VERSION 5.7 ;
  NOWIREEXTENSIONATPIN ON ;
  DIVIDERCHAR "/" ;
  BUSBITCHARS "[]" ;
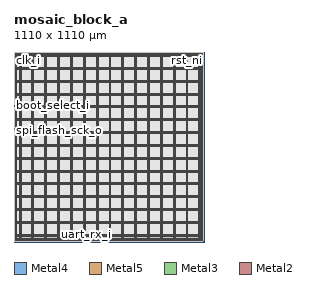
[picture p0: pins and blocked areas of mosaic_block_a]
MACRO mosaic_block_a
  CLASS BLOCK ;
  FOREIGN mosaic_block_a ;
  ORIGIN 0.000 0.000 ;
  SIZE 1110.000 BY 1110.000 ;
  PIN VDD
    DIRECTION INOUT ;
    USE POWER ;
    PORT
      LAYER Metal4 ;
        RECT 11.240 14.600 14.240 1098.680 ;
    END
    PORT
      LAYER Metal4 ;
        RECT 1095.680 14.600 1098.680 1098.680 ;
    END
    PORT
      LAYER Metal5 ;
        RECT 11.240 14.600 1098.680 17.600 ;
    END
    PORT
      LAYER Metal5 ;
        RECT 11.240 1095.680 1098.680 1098.680 ;
    END
    PORT
      LAYER Metal4 ;
        RECT 30.060 9.600 35.060 1103.680 ;
    END
    PORT
      LAYER Metal4 ;
        RECT 105.060 9.600 110.060 1103.680 ;
    END
    PORT
      LAYER Metal4 ;
        RECT 180.060 9.600 185.060 1103.680 ;
    END
    PORT
      LAYER Metal4 ;
        RECT 255.060 9.600 260.060 1103.680 ;
    END
    PORT
      LAYER Metal4 ;
        RECT 330.060 9.600 335.060 1103.680 ;
    END
    PORT
      LAYER Metal4 ;
        RECT 405.060 9.600 410.060 1103.680 ;
    END
    PORT
      LAYER Metal4 ;
        RECT 480.060 9.600 485.060 1103.680 ;
    END
    PORT
      LAYER Metal4 ;
        RECT 555.060 9.600 560.060 1103.680 ;
    END
    PORT
      LAYER Metal4 ;
        RECT 630.060 9.600 635.060 1103.680 ;
    END
    PORT
      LAYER Metal4 ;
        RECT 705.060 9.600 710.060 1103.680 ;
    END
    PORT
      LAYER Metal4 ;
        RECT 780.060 9.600 785.060 1103.680 ;
    END
    PORT
      LAYER Metal4 ;
        RECT 855.060 9.600 860.060 1103.680 ;
    END
    PORT
      LAYER Metal4 ;
        RECT 930.060 9.600 935.060 1103.680 ;
    END
    PORT
      LAYER Metal4 ;
        RECT 1005.060 9.600 1010.060 1103.680 ;
    END
    PORT
      LAYER Metal4 ;
        RECT 1080.060 9.600 1085.060 1103.680 ;
    END
    PORT
      LAYER Metal5 ;
        RECT 6.240 33.750 1103.680 38.750 ;
    END
    PORT
      LAYER Metal5 ;
        RECT 6.240 108.750 1103.680 113.750 ;
    END
    PORT
      LAYER Metal5 ;
        RECT 6.240 183.750 1103.680 188.750 ;
    END
    PORT
      LAYER Metal5 ;
        RECT 6.240 258.750 1103.680 263.750 ;
    END
    PORT
      LAYER Metal5 ;
        RECT 6.240 333.750 1103.680 338.750 ;
    END
    PORT
      LAYER Metal5 ;
        RECT 6.240 408.750 1103.680 413.750 ;
    END
    PORT
      LAYER Metal5 ;
        RECT 6.240 483.750 1103.680 488.750 ;
    END
    PORT
      LAYER Metal5 ;
        RECT 6.240 558.750 1103.680 563.750 ;
    END
    PORT
      LAYER Metal5 ;
        RECT 6.240 633.750 1103.680 638.750 ;
    END
    PORT
      LAYER Metal5 ;
        RECT 6.240 708.750 1103.680 713.750 ;
    END
    PORT
      LAYER Metal5 ;
        RECT 6.240 783.750 1103.680 788.750 ;
    END
    PORT
      LAYER Metal5 ;
        RECT 6.240 858.750 1103.680 863.750 ;
    END
    PORT
      LAYER Metal5 ;
        RECT 6.240 933.750 1103.680 938.750 ;
    END
    PORT
      LAYER Metal5 ;
        RECT 6.240 1008.750 1103.680 1013.750 ;
    END
    PORT
      LAYER Metal5 ;
        RECT 6.240 1083.750 1103.680 1088.750 ;
    END
  END VDD
  PIN VSS
    DIRECTION INOUT ;
    USE GROUND ;
    PORT
      LAYER Metal4 ;
        RECT 6.240 9.600 9.240 1103.680 ;
    END
    PORT
      LAYER Metal4 ;
        RECT 1100.680 9.600 1103.680 1103.680 ;
    END
    PORT
      LAYER Metal5 ;
        RECT 6.240 9.600 1103.680 12.600 ;
    END
    PORT
      LAYER Metal5 ;
        RECT 6.240 1100.680 1103.680 1103.680 ;
    END
    PORT
      LAYER Metal4 ;
        RECT 36.060 9.600 41.060 1103.680 ;
    END
    PORT
      LAYER Metal4 ;
        RECT 111.060 9.600 116.060 1103.680 ;
    END
    PORT
      LAYER Metal4 ;
        RECT 186.060 9.600 191.060 1103.680 ;
    END
    PORT
      LAYER Metal4 ;
        RECT 261.060 9.600 266.060 1103.680 ;
    END
    PORT
      LAYER Metal4 ;
        RECT 336.060 9.600 341.060 1103.680 ;
    END
    PORT
      LAYER Metal4 ;
        RECT 411.060 9.600 416.060 1103.680 ;
    END
    PORT
      LAYER Metal4 ;
        RECT 486.060 9.600 491.060 1103.680 ;
    END
    PORT
      LAYER Metal4 ;
        RECT 561.060 9.600 566.060 1103.680 ;
    END
    PORT
      LAYER Metal4 ;
        RECT 636.060 9.600 641.060 1103.680 ;
    END
    PORT
      LAYER Metal4 ;
        RECT 711.060 9.600 716.060 1103.680 ;
    END
    PORT
      LAYER Metal4 ;
        RECT 786.060 9.600 791.060 1103.680 ;
    END
    PORT
      LAYER Metal4 ;
        RECT 861.060 9.600 866.060 1103.680 ;
    END
    PORT
      LAYER Metal4 ;
        RECT 936.060 9.600 941.060 1103.680 ;
    END
    PORT
      LAYER Metal4 ;
        RECT 1011.060 9.600 1016.060 1103.680 ;
    END
    PORT
      LAYER Metal4 ;
        RECT 1086.060 9.600 1091.060 1103.680 ;
    END
    PORT
      LAYER Metal5 ;
        RECT 6.240 39.750 1103.680 44.750 ;
    END
    PORT
      LAYER Metal5 ;
        RECT 6.240 114.750 1103.680 119.750 ;
    END
    PORT
      LAYER Metal5 ;
        RECT 6.240 189.750 1103.680 194.750 ;
    END
    PORT
      LAYER Metal5 ;
        RECT 6.240 264.750 1103.680 269.750 ;
    END
    PORT
      LAYER Metal5 ;
        RECT 6.240 339.750 1103.680 344.750 ;
    END
    PORT
      LAYER Metal5 ;
        RECT 6.240 414.750 1103.680 419.750 ;
    END
    PORT
      LAYER Metal5 ;
        RECT 6.240 489.750 1103.680 494.750 ;
    END
    PORT
      LAYER Metal5 ;
        RECT 6.240 564.750 1103.680 569.750 ;
    END
    PORT
      LAYER Metal5 ;
        RECT 6.240 639.750 1103.680 644.750 ;
    END
    PORT
      LAYER Metal5 ;
        RECT 6.240 714.750 1103.680 719.750 ;
    END
    PORT
      LAYER Metal5 ;
        RECT 6.240 789.750 1103.680 794.750 ;
    END
    PORT
      LAYER Metal5 ;
        RECT 6.240 864.750 1103.680 869.750 ;
    END
    PORT
      LAYER Metal5 ;
        RECT 6.240 939.750 1103.680 944.750 ;
    END
    PORT
      LAYER Metal5 ;
        RECT 6.240 1014.750 1103.680 1019.750 ;
    END
    PORT
      LAYER Metal5 ;
        RECT 6.240 1089.750 1103.680 1094.750 ;
    END
  END VSS
  PIN boot_select_i
    DIRECTION INPUT ;
    USE SIGNAL ;
    ANTENNAGATEAREA 0.396000 ;
    PORT
      LAYER Metal3 ;
        RECT 0.000 796.320 0.560 796.880 ;
    END
  END boot_select_i
  PIN clk_i
    DIRECTION INPUT ;
    USE SIGNAL ;
    ANTENNAGATEAREA 9.476000 ;
    PORT
      LAYER Metal3 ;
        RECT 0.000 1087.520 0.560 1088.080 ;
    END
  END clk_i
  PIN execute_from_flash_i
    DIRECTION INPUT ;
    USE SIGNAL ;
    ANTENNAGATEAREA 0.396000 ;
    PORT
      LAYER Metal3 ;
        RECT 0.000 778.400 0.560 778.960 ;
    END
  END execute_from_flash_i
  PIN rst_ni
    DIRECTION INPUT ;
    USE SIGNAL ;
    ANTENNAGATEAREA 0.396000 ;
    PORT
      LAYER Metal2 ;
        RECT 1030.400 1109.440 1030.960 1110.000 ;
    END
  END rst_ni
  PIN spi_flash_cs_o
    DIRECTION OUTPUT ;
    USE SIGNAL ;
    ANTENNADIFFAREA 0.897600 ;
    PORT
      LAYER Metal3 ;
        RECT 0.000 658.560 0.560 659.120 ;
    END
  END spi_flash_cs_o
  PIN spi_flash_sck_o
    DIRECTION OUTPUT ;
    USE SIGNAL ;
    ANTENNADIFFAREA 0.897600 ;
    PORT
      LAYER Metal3 ;
        RECT 0.000 649.600 0.560 650.160 ;
    END
  END spi_flash_sck_o
  PIN spi_flash_sd_io[0]
    DIRECTION INOUT ;
    USE SIGNAL ;
    ANTENNAGATEAREA 2.204000 ;
    ANTENNADIFFAREA 2.074800 ;
    PORT
      LAYER Metal3 ;
        RECT 0.000 659.680 0.560 660.240 ;
    END
  END spi_flash_sd_io[0]
  PIN spi_flash_sd_io[1]
    DIRECTION INOUT ;
    USE SIGNAL ;
    ANTENNAGATEAREA 2.204000 ;
    ANTENNADIFFAREA 2.074800 ;
    PORT
      LAYER Metal3 ;
        RECT 0.000 657.440 0.560 658.000 ;
    END
  END spi_flash_sd_io[1]
  PIN spi_flash_sd_io[2]
    DIRECTION INOUT ;
    USE SIGNAL ;
    ANTENNAGATEAREA 2.204000 ;
    ANTENNADIFFAREA 2.074800 ;
    PORT
      LAYER Metal3 ;
        RECT 0.000 656.320 0.560 656.880 ;
    END
  END spi_flash_sd_io[2]
  PIN spi_flash_sd_io[3]
    DIRECTION INOUT ;
    USE SIGNAL ;
    ANTENNAGATEAREA 2.204000 ;
    ANTENNADIFFAREA 2.074800 ;
    PORT
      LAYER Metal3 ;
        RECT 0.000 652.960 0.560 653.520 ;
    END
  END spi_flash_sd_io[3]
  PIN status_o[0]
    DIRECTION OUTPUT ;
    USE SIGNAL ;
    ANTENNADIFFAREA 0.897600 ;
    PORT
      LAYER Metal3 ;
        RECT 0.000 795.200 0.560 795.760 ;
    END
  END status_o[0]
  PIN status_o[1]
    DIRECTION OUTPUT ;
    USE SIGNAL ;
    ANTENNADIFFAREA 0.897600 ;
    PORT
      LAYER Metal3 ;
        RECT 0.000 803.040 0.560 803.600 ;
    END
  END status_o[1]
  PIN status_o[2]
    DIRECTION OUTPUT ;
    USE SIGNAL ;
    ANTENNADIFFAREA 0.897600 ;
    PORT
      LAYER Metal3 ;
        RECT 0.000 801.920 0.560 802.480 ;
    END
  END status_o[2]
  PIN status_o[3]
    DIRECTION OUTPUT ;
    USE SIGNAL ;
    ANTENNADIFFAREA 0.897600 ;
    PORT
      LAYER Metal3 ;
        RECT 0.000 736.960 0.560 737.520 ;
    END
  END status_o[3]
  PIN status_o[4]
    DIRECTION OUTPUT ;
    USE SIGNAL ;
    ANTENNADIFFAREA 0.897600 ;
    PORT
      LAYER Metal3 ;
        RECT 0.000 769.440 0.560 770.000 ;
    END
  END status_o[4]
  PIN status_o[5]
    DIRECTION OUTPUT ;
    USE SIGNAL ;
    ANTENNADIFFAREA 0.897600 ;
    PORT
      LAYER Metal3 ;
        RECT 0.000 743.680 0.560 744.240 ;
    END
  END status_o[5]
  PIN status_o[6]
    DIRECTION OUTPUT ;
    USE SIGNAL ;
    ANTENNADIFFAREA 0.897600 ;
    PORT
      LAYER Metal3 ;
        RECT 0.000 804.160 0.560 804.720 ;
    END
  END status_o[6]
  PIN status_valid_o
    DIRECTION OUTPUT ;
    USE SIGNAL ;
    ANTENNADIFFAREA 0.897600 ;
    PORT
      LAYER Metal3 ;
        RECT 0.000 794.080 0.560 794.640 ;
    END
  END status_valid_o
  PIN uart_rx_i
    DIRECTION INPUT ;
    USE SIGNAL ;
    ANTENNAGATEAREA 0.498500 ;
    PORT
      LAYER Metal2 ;
        RECT 423.360 0.000 423.920 0.560 ;
    END
  END uart_rx_i
  PIN uart_tx_o
    DIRECTION OUTPUT ;
    USE SIGNAL ;
    ANTENNADIFFAREA 0.897600 ;
    PORT
      LAYER Metal2 ;
        RECT 421.120 0.000 421.680 0.560 ;
    END
  END uart_tx_o
  OBS
      LAYER Nwell ;
        RECT 15.810 19.170 1094.110 1094.110 ;
      LAYER Metal1 ;
        RECT 16.240 19.300 1093.680 1093.980 ;
      LAYER Metal2 ;
        RECT 3.500 1109.140 1030.100 1109.440 ;
        RECT 1031.260 1109.140 1102.500 1109.440 ;
        RECT 3.500 0.860 1102.500 1109.140 ;
        RECT 3.500 0.560 420.820 0.860 ;
        RECT 421.980 0.560 423.060 0.860 ;
        RECT 424.220 0.560 1102.500 0.860 ;
      LAYER Metal3 ;
        RECT 0.560 1088.380 1104.790 1105.860 ;
        RECT 0.860 1087.220 1104.790 1088.380 ;
        RECT 0.560 805.020 1104.790 1087.220 ;
        RECT 0.860 801.620 1104.790 805.020 ;
        RECT 0.560 797.180 1104.790 801.620 ;
        RECT 0.860 793.780 1104.790 797.180 ;
        RECT 0.560 779.260 1104.790 793.780 ;
        RECT 0.860 778.100 1104.790 779.260 ;
        RECT 0.560 770.300 1104.790 778.100 ;
        RECT 0.860 769.140 1104.790 770.300 ;
        RECT 0.560 744.540 1104.790 769.140 ;
        RECT 0.860 743.380 1104.790 744.540 ;
        RECT 0.560 737.820 1104.790 743.380 ;
        RECT 0.860 736.660 1104.790 737.820 ;
        RECT 0.560 660.540 1104.790 736.660 ;
        RECT 0.860 656.020 1104.790 660.540 ;
        RECT 0.560 653.820 1104.790 656.020 ;
        RECT 0.860 652.660 1104.790 653.820 ;
        RECT 0.560 650.460 1104.790 652.660 ;
        RECT 0.860 649.300 1104.790 650.460 ;
        RECT 0.560 10.780 1104.790 649.300 ;
      LAYER Metal4 ;
        RECT 2.940 1103.980 1104.740 1104.940 ;
        RECT 2.940 19.690 5.940 1103.980 ;
        RECT 9.540 1098.980 29.760 1103.980 ;
        RECT 9.540 19.690 10.940 1098.980 ;
        RECT 14.540 19.690 29.760 1098.980 ;
        RECT 35.360 19.690 35.760 1103.980 ;
        RECT 41.360 19.690 104.760 1103.980 ;
        RECT 110.360 19.690 110.760 1103.980 ;
        RECT 116.360 19.690 179.760 1103.980 ;
        RECT 185.360 19.690 185.760 1103.980 ;
        RECT 191.360 19.690 254.760 1103.980 ;
        RECT 260.360 19.690 260.760 1103.980 ;
        RECT 266.360 19.690 329.760 1103.980 ;
        RECT 335.360 19.690 335.760 1103.980 ;
        RECT 341.360 19.690 404.760 1103.980 ;
        RECT 410.360 19.690 410.760 1103.980 ;
        RECT 416.360 19.690 479.760 1103.980 ;
        RECT 485.360 19.690 485.760 1103.980 ;
        RECT 491.360 19.690 554.760 1103.980 ;
        RECT 560.360 19.690 560.760 1103.980 ;
        RECT 566.360 19.690 629.760 1103.980 ;
        RECT 635.360 19.690 635.760 1103.980 ;
        RECT 641.360 19.690 704.760 1103.980 ;
        RECT 710.360 19.690 710.760 1103.980 ;
        RECT 716.360 19.690 779.760 1103.980 ;
        RECT 785.360 19.690 785.760 1103.980 ;
        RECT 791.360 19.690 854.760 1103.980 ;
        RECT 860.360 19.690 860.760 1103.980 ;
        RECT 866.360 19.690 929.760 1103.980 ;
        RECT 935.360 19.690 935.760 1103.980 ;
        RECT 941.360 19.690 1004.760 1103.980 ;
        RECT 1010.360 19.690 1010.760 1103.980 ;
        RECT 1016.360 19.690 1079.760 1103.980 ;
        RECT 1085.360 19.690 1085.760 1103.980 ;
        RECT 1091.360 1098.980 1100.380 1103.980 ;
        RECT 1091.360 19.690 1095.380 1098.980 ;
        RECT 1098.980 19.690 1100.380 1098.980 ;
        RECT 1103.980 19.690 1104.740 1103.980 ;
      LAYER Metal5 ;
        RECT 2.860 1104.280 1104.820 1104.970 ;
        RECT 2.860 1100.080 5.640 1104.280 ;
        RECT 1104.280 1100.080 1104.820 1104.280 ;
        RECT 2.860 1099.280 1104.820 1100.080 ;
        RECT 2.860 1095.350 10.640 1099.280 ;
        RECT 1099.280 1095.350 1104.820 1099.280 ;
        RECT 2.860 1083.150 5.640 1095.350 ;
        RECT 1104.280 1083.150 1104.820 1095.350 ;
        RECT 2.860 1020.350 1104.820 1083.150 ;
        RECT 2.860 1008.150 5.640 1020.350 ;
        RECT 1104.280 1008.150 1104.820 1020.350 ;
        RECT 2.860 945.350 1104.820 1008.150 ;
        RECT 2.860 933.150 5.640 945.350 ;
        RECT 1104.280 933.150 1104.820 945.350 ;
        RECT 2.860 870.350 1104.820 933.150 ;
        RECT 2.860 858.150 5.640 870.350 ;
        RECT 1104.280 858.150 1104.820 870.350 ;
        RECT 2.860 795.350 1104.820 858.150 ;
        RECT 2.860 783.150 5.640 795.350 ;
        RECT 1104.280 783.150 1104.820 795.350 ;
        RECT 2.860 720.350 1104.820 783.150 ;
        RECT 2.860 708.150 5.640 720.350 ;
        RECT 1104.280 708.150 1104.820 720.350 ;
        RECT 2.860 645.350 1104.820 708.150 ;
        RECT 2.860 633.150 5.640 645.350 ;
        RECT 1104.280 633.150 1104.820 645.350 ;
        RECT 2.860 570.350 1104.820 633.150 ;
        RECT 2.860 558.150 5.640 570.350 ;
        RECT 1104.280 558.150 1104.820 570.350 ;
        RECT 2.860 495.350 1104.820 558.150 ;
        RECT 2.860 483.150 5.640 495.350 ;
        RECT 1104.280 483.150 1104.820 495.350 ;
        RECT 2.860 420.350 1104.820 483.150 ;
        RECT 2.860 408.150 5.640 420.350 ;
        RECT 1104.280 408.150 1104.820 420.350 ;
        RECT 2.860 345.350 1104.820 408.150 ;
        RECT 2.860 333.150 5.640 345.350 ;
        RECT 1104.280 333.150 1104.820 345.350 ;
        RECT 2.860 270.350 1104.820 333.150 ;
        RECT 2.860 258.150 5.640 270.350 ;
        RECT 1104.280 258.150 1104.820 270.350 ;
        RECT 2.860 195.350 1104.820 258.150 ;
        RECT 2.860 183.150 5.640 195.350 ;
        RECT 1104.280 183.150 1104.820 195.350 ;
        RECT 2.860 120.350 1104.820 183.150 ;
        RECT 2.860 108.150 5.640 120.350 ;
        RECT 1104.280 108.150 1104.820 120.350 ;
        RECT 2.860 45.350 1104.820 108.150 ;
        RECT 2.860 33.150 5.640 45.350 ;
        RECT 1104.280 33.150 1104.820 45.350 ;
        RECT 2.860 28.130 1104.820 33.150 ;
  END
END mosaic_block_a
END LIBRARY

